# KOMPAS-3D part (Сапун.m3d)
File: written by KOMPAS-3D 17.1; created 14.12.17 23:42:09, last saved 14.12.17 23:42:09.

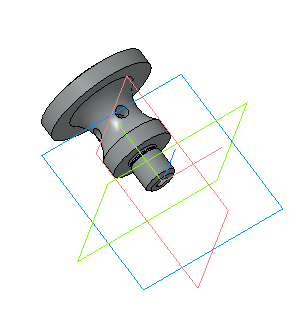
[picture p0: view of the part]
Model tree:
1. Операция без истории:1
